One B-rep face of a CAD part: STEP entity #515.
In plain terms, the planar face has unit normal (1, 0, 0).
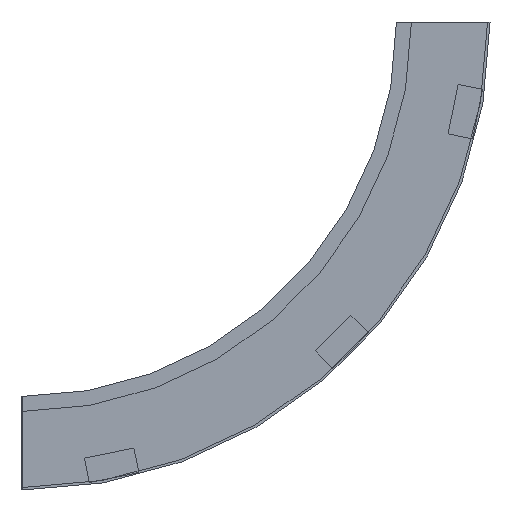
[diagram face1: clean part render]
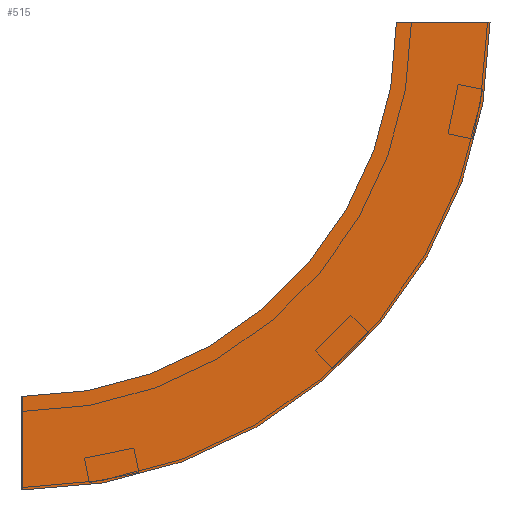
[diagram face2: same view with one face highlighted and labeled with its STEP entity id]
Its self-contained STEP definition (entity closure, numbers rounded to 3 decimals):
#11 = AXIS2_PLACEMENT_3D ( 'NONE', #289, #468, #313 ) ;
#30 = AXIS2_PLACEMENT_3D ( 'NONE', #505, #48, #190 ) ;
#48 = DIRECTION ( 'NONE',  ( 1., 0., 0. ) ) ;
#49 = VERTEX_POINT ( 'NONE', #424 ) ;
#58 = EDGE_CURVE ( 'NONE', #563, #49, #209, .T. ) ;
#70 = DIRECTION ( 'NONE',  ( 0., -1., 0. ) ) ;
#94 = CARTESIAN_POINT ( 'NONE',  ( 0., 300., -375. ) ) ;
#110 = PLANE ( 'NONE',  #11 ) ;
#115 = VECTOR ( 'NONE', #278, 1000. ) ;
#119 = VECTOR ( 'NONE', #480, 1000. ) ;
#133 = CARTESIAN_POINT ( 'NONE',  ( 0., -75., 0. ) ) ;
#156 = CARTESIAN_POINT ( 'NONE',  ( 0., -75., 0. ) ) ;
#159 = EDGE_CURVE ( 'NONE', #49, #511, #165, .T. ) ;
#165 = CIRCLE ( 'NONE', #518, 300. ) ;
#173 = ORIENTED_EDGE ( 'NONE', *, *, #406, .T. ) ;
#190 = DIRECTION ( 'NONE',  ( 0., -1., 0. ) ) ;
#196 = EDGE_LOOP ( 'NONE', ( #335, #557, #173, #373 ) ) ;
#209 = LINE ( 'NONE', #156, #119 ) ;
#223 = CARTESIAN_POINT ( 'NONE',  ( 0., 300., -375. ) ) ;
#237 = VERTEX_POINT ( 'NONE', #223 ) ;
#247 = FACE_OUTER_BOUND ( 'NONE', #196, .T. ) ;
#278 = DIRECTION ( 'NONE',  ( 0., 0., 1. ) ) ;
#288 = CARTESIAN_POINT ( 'NONE',  ( 0., 300., -300. ) ) ;
#289 = CARTESIAN_POINT ( 'NONE',  ( 0., -75., 0. ) ) ;
#291 = CIRCLE ( 'NONE', #30, 375. ) ;
#313 = DIRECTION ( 'NONE',  ( 0., 0., 1. ) ) ;
#335 = ORIENTED_EDGE ( 'NONE', *, *, #159, .F. ) ;
#373 = ORIENTED_EDGE ( 'NONE', *, *, #399, .T. ) ;
#389 = CARTESIAN_POINT ( 'NONE',  ( 0., 300., 0. ) ) ;
#399 = EDGE_CURVE ( 'NONE', #237, #511, #404, .T. ) ;
#404 = LINE ( 'NONE', #94, #115 ) ;
#406 = EDGE_CURVE ( 'NONE', #563, #237, #291, .T. ) ;
#424 = CARTESIAN_POINT ( 'NONE',  ( 0., 0., 0. ) ) ;
#468 = DIRECTION ( 'NONE',  ( -1., 0., 0. ) ) ;
#480 = DIRECTION ( 'NONE',  ( 0., 1., 0. ) ) ;
#505 = CARTESIAN_POINT ( 'NONE',  ( 0., 300., 0. ) ) ;
#511 = VERTEX_POINT ( 'NONE', #288 ) ;
#515 = ADVANCED_FACE ( 'NONE', ( #247 ), #110, .F. ) ;
#518 = AXIS2_PLACEMENT_3D ( 'NONE', #389, #569, #70 ) ;
#557 = ORIENTED_EDGE ( 'NONE', *, *, #58, .F. ) ;
#563 = VERTEX_POINT ( 'NONE', #133 ) ;
#569 = DIRECTION ( 'NONE',  ( 1., 0., 0. ) ) ;
